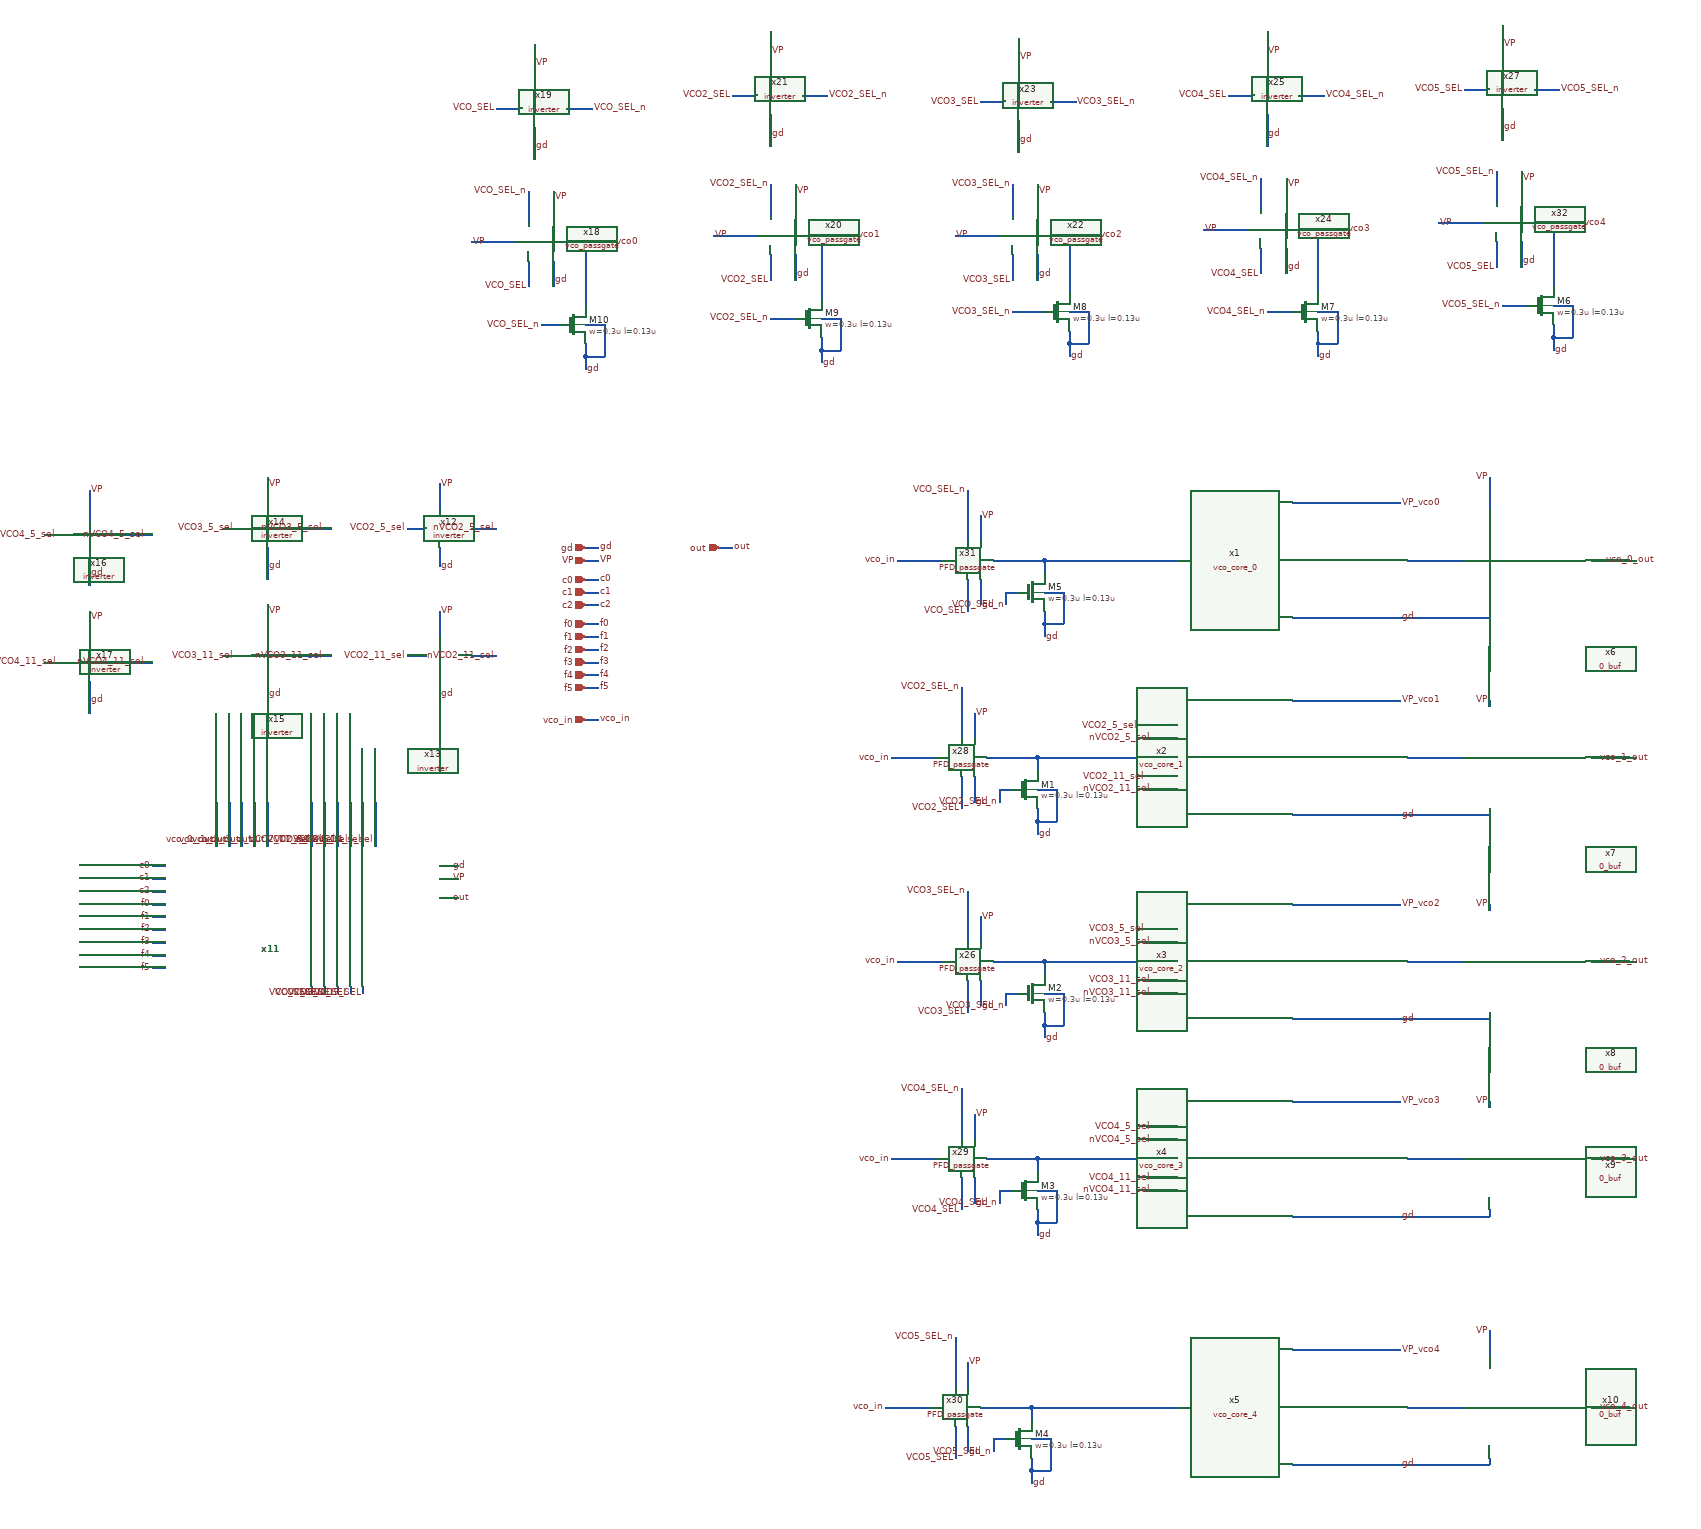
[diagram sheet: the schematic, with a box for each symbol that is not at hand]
v {xschem version=3.4.8RC file_version=1.3}
G {}
K {}
V {}
S {}
F {}
E {}
N 230 -210 320 -210 {lab=#net1}
N 230 100 320 100 {lab=#net2}
N 230 420 320 420 {lab=#net3}
N 230 730 320 730 {lab=#net4}
N 230 1120 320 1120 {lab=#net5}
N 520 -210 580 -210 {lab=vco_0_out}
N 520 100 580 100 {lab=vco_1_out}
N 520 420 580 420 {lab=vco_2_out}
N 520 730 580 730 {lab=vco_3_out}
N 520 1120 580 1120 {lab=vco_4_out}
N -1060 -230 -1040 -230 {lab=gd}
N -1060 -210 -1040 -210 {lab=VP}
N -1060 -160 -1040 -160 {lab=c1}
N -1060 -140 -1040 -140 {lab=c2}
N -1060 -110 -1040 -110 {lab=f0}
N -1060 -90 -1040 -90 {lab=f1}
N -1060 -180 -1040 -180 {lab=c0}
N -1060 -70 -1040 -70 {lab=f2}
N -1060 -50 -1040 -50 {lab=f3}
N -1060 -30 -1040 -30 {lab=f4}
N -1060 -10 -1040 -10 {lab=f5}
N -1290 270 -1270 270 {lab=gd}
N -1290 290 -1270 290 {lab=VP}
N -850 -230 -830 -230 {lab=out}
N -1290 320 -1270 320 {lab=out}
N 50 -120 360 -120 {lab=gd}
N 360 -130 360 -120 {lab=gd}
N 50 190 360 190 {lab=gd}
N 360 180 360 190 {lab=gd}
N 50 510 360 510 {lab=gd}
N 360 500 360 510 {lab=gd}
N 360 810 360 820 {lab=gd}
N 50 1210 360 1210 {lab=gd}
N 360 1200 360 1210 {lab=gd}
N 360 640 360 650 {lab=VP}
N 360 330 360 340 {lab=VP}
N 360 10 360 20 {lab=VP}
N -180 130 -130 130 {lab=VCO2_11_sel}
N -180 150 -130 150 {lab=nVCO2_11_sel}
N -180 470 -130 470 {lab=nVCO3_11_sel}
N -180 780 -130 780 {lab=nVCO4_11_sel}
N -1490 170 -1490 240 {lab=VCO2_11_sel}
N -1470 170 -1470 240 {lab=VCO2_5_sel}
N -1450 170 -1450 240 {lab=VCO3_11_sel}
N -1430 170 -1430 240 {lab=VCO3_5_sel}
N -1410 170 -1410 240 {lab=VCO4_11_sel}
N -1390 170 -1390 240 {lab=VCO4_5_sel}
N -1640 170 -1640 240 {lab=vco_0_out}
N -1620 170 -1620 240 {lab=vco_1_out}
N -1600 170 -1600 240 {lab=vco_2_out}
N -1580 170 -1580 240 {lab=vco_3_out}
N -1560 170 -1560 240 {lab=vco_4_out}
N -1740 290 -1720 290 {lab=c1}
N -1740 310 -1720 310 {lab=c2}
N -1740 330 -1720 330 {lab=f0}
N -1740 350 -1720 350 {lab=f1}
N -1740 270 -1720 270 {lab=c0}
N -1740 370 -1720 370 {lab=f2}
N -1740 390 -1720 390 {lab=f3}
N -1740 410 -1720 410 {lab=f4}
N -1740 430 -1720 430 {lab=f5}
N -1060 40 -1040 40 {lab=vco_in}
N 50 820 360 820 {lab=gd}
N -180 70 -130 70 {lab=nVCO2_5_sel}
N -180 370 -130 370 {lab=VCO3_5_sel}
N -180 390 -130 390 {lab=nVCO3_5_sel}
N -1560 -340 -1560 -290 {lab=VP}
N -1560 -230 -1560 -180 {lab=gd}
N -1510 -260 -1460 -260 {lab=nVCO3_5_sel}
N -1630 -260 -1580 -260 {lab=VCO3_5_sel}
N -1560 -140 -1560 -90 {lab=VP}
N -1560 -30 -1560 20 {lab=gd}
N -1510 -60 -1460 -60 {lab=nVCO3_11_sel}
N -1630 -60 -1580 -60 {lab=VCO3_11_sel}
N -180 680 -130 680 {lab=VCO4_5_sel}
N -180 760 -130 760 {lab=VCO4_11_sel}
N -180 700 -130 700 {lab=nVCO4_5_sel}
N -1840 -220 -1840 -170 {lab=gd}
N -1790 -250 -1740 -250 {lab=nVCO4_5_sel}
N -1910 -250 -1860 -250 {lab=VCO4_5_sel}
N -1840 -130 -1840 -80 {lab=VP}
N -1840 -20 -1840 30 {lab=gd}
N -1790 -50 -1740 -50 {lab=nVCO4_11_sel}
N -1910 -50 -1860 -50 {lab=VCO4_11_sel}
N -1840 -320 -1840 -270 {lab=VP}
N -190 50 -130 50 {lab=VCO2_5_sel}
N -180 450 -130 450 {lab=VCO3_11_sel}
N -1290 -30 -1290 0 {lab=gd}
N -1340 -60 -1310 -60 {lab=VCO2_11_sel}
N -1240 -60 -1200 -60 {lab=nVCO2_11_sel}
N -1290 -130 -1290 -90 {lab=VP}
N -1290 -230 -1290 -200 {lab=gd}
N -1340 -260 -1310 -260 {lab=VCO2_5_sel}
N -1240 -260 -1200 -260 {lab=nVCO2_5_sel}
N -1290 -330 -1290 -290 {lab=VP}
N -1240 -710 -1170 -710 {lab=VP}
N -1060 -710 -1010 -710 {lab=VP_vco0}
N -1200 -920 -1160 -920 {lab=VCO_SEL}
N -1140 -890 -1140 -840 {lab=gd}
N -1140 -1020 -1140 -950 {lab=VP}
N -1090 -920 -1050 -920 {lab=VCO_SEL_n}
N -1150 -680 -1150 -640 {lab=VCO_SEL}
N -1150 -790 -1150 -740 {lab=VCO_SEL_n}
N -1110 -790 -1110 -740 {lab=VP}
N -1110 -680 -1110 -640 {lab=gd}
N -860 -720 -790 -720 {lab=VP}
N -690 -720 -630 -720 {lab=VP_vco1}
N -830 -940 -790 -940 {lab=VCO2_SEL}
N -770 -910 -770 -860 {lab=gd}
N -770 -1040 -770 -970 {lab=VP}
N -720 -940 -680 -940 {lab=VCO2_SEL_n}
N -770 -690 -770 -650 {lab=VCO2_SEL}
N -770 -800 -770 -750 {lab=VCO2_SEL_n}
N -730 -800 -730 -750 {lab=VP}
N -730 -690 -730 -650 {lab=gd}
N -480 -720 -410 -720 {lab=VP}
N -300 -720 -250 -720 {lab=VP_vco2}
N -440 -930 -400 -930 {lab=VCO3_SEL}
N -380 -900 -380 -850 {lab=gd}
N -380 -1030 -380 -960 {lab=VP}
N -330 -930 -290 -930 {lab=VCO3_SEL_n}
N -390 -690 -390 -650 {lab=VCO3_SEL}
N -390 -800 -390 -750 {lab=VCO3_SEL_n}
N -350 -800 -350 -750 {lab=VP}
N -350 -690 -350 -650 {lab=gd}
N -90 -730 -20 -730 {lab=VP}
N 90 -730 140 -730 {lab=VP_vco3}
N -50 -940 -10 -940 {lab=VCO4_SEL}
N 10 -910 10 -860 {lab=gd}
N 10 -1040 10 -970 {lab=VP}
N 60 -940 100 -940 {lab=VCO4_SEL_n}
N 0 -700 0 -660 {lab=VCO4_SEL}
N 0 -810 0 -760 {lab=VCO4_SEL_n}
N 40 -810 40 -760 {lab=VP}
N 40 -700 40 -660 {lab=gd}
N 280 -740 350 -740 {lab=VP}
N 460 -740 510 -740 {lab=VP_vco4}
N 320 -950 360 -950 {lab=VCO5_SEL}
N 380 -920 380 -870 {lab=gd}
N 380 -1050 380 -980 {lab=VP}
N 430 -950 470 -950 {lab=VCO5_SEL_n}
N 370 -710 370 -670 {lab=VCO5_SEL}
N 370 -820 370 -770 {lab=VCO5_SEL_n}
N 410 -820 410 -770 {lab=VP}
N 410 -710 410 -670 {lab=gd}
N 50 -300 220 -300 {lab=VP_vco0}
N 360 -340 360 -290 {lab=VP}
N 50 10 220 10 {lab=VP_vco1}
N 50 330 220 330 {lab=VP_vco2}
N 50 640 220 640 {lab=VP_vco3}
N 50 1030 220 1030 {lab=VP_vco4}
N 360 1000 360 1040 {lab=VP}
N -580 100 -510 100 {lab=vco_in}
N -350 100 -130 100 {lab=#net6}
N -450 30 -450 70 {lab=VP}
N -450 130 -450 170 {lab=gd}
N -350 100 -350 120 {lab=#net6}
N -430 100 -350 100 {lab=#net6}
N -410 150 -390 150 {lab=VCO2_SEL_n}
N -350 200 -350 220 {lab=gd}
N -350 200 -320 200 {lab=gd}
N -350 180 -350 200 {lab=gd}
N -320 150 -320 200 {lab=gd}
N -350 150 -320 150 {lab=gd}
N -470 130 -470 180 {lab=VCO2_SEL}
N -340 420 -130 420 {lab=#net7}
N -350 730 -130 730 {lab=#net8}
N -360 1120 -130 1120 {lab=#net9}
N -470 -10 -470 70 {lab=VCO2_SEL_n}
N 460 -560 460 -540 {lab=gd}
N 460 -560 490 -560 {lab=gd}
N 460 -580 460 -560 {lab=gd}
N 490 -610 490 -560 {lab=gd}
N 460 -610 490 -610 {lab=gd}
N 460 -740 460 -640 {lab=VP_vco4}
N 430 -740 460 -740 {lab=VP_vco4}
N 90 -550 90 -530 {lab=gd}
N 90 -550 120 -550 {lab=gd}
N 90 -570 90 -550 {lab=gd}
N 120 -600 120 -550 {lab=gd}
N 90 -600 120 -600 {lab=gd}
N 90 -730 90 -630 {lab=VP_vco3}
N 60 -730 90 -730 {lab=VP_vco3}
N -300 -550 -300 -530 {lab=gd}
N -300 -550 -270 -550 {lab=gd}
N -300 -570 -300 -550 {lab=gd}
N -270 -600 -270 -550 {lab=gd}
N -300 -600 -270 -600 {lab=gd}
N -690 -540 -690 -520 {lab=gd}
N -690 -540 -660 -540 {lab=gd}
N -690 -560 -690 -540 {lab=gd}
N -660 -590 -660 -540 {lab=gd}
N -690 -590 -660 -590 {lab=gd}
N -690 -720 -690 -620 {lab=VP_vco1}
N -710 -720 -690 -720 {lab=VP_vco1}
N -1060 -530 -1060 -510 {lab=gd}
N -1060 -530 -1030 -530 {lab=gd}
N -1060 -550 -1060 -530 {lab=gd}
N -1030 -580 -1030 -530 {lab=gd}
N -1060 -580 -1030 -580 {lab=gd}
N -1060 -710 -1060 -610 {lab=VP_vco0}
N -1090 -710 -1060 -710 {lab=VP_vco0}
N -1130 -580 -1100 -580 {lab=VCO_SEL_n}
N -770 -590 -730 -590 {lab=VCO2_SEL_n}
N -390 -600 -340 -600 {lab=VCO3_SEL_n}
N 10 -600 50 -600 {lab=VCO4_SEL_n}
N 380 -610 420 -610 {lab=VCO5_SEL_n}
N -300 -720 -300 -630 {lab=VP_vco2}
N -330 -720 -300 -720 {lab=VP_vco2}
N -410 150 -410 170 {lab=VCO2_SEL_n}
N -570 420 -500 420 {lab=vco_in}
N -440 350 -440 390 {lab=VP}
N -440 450 -440 490 {lab=gd}
N -340 420 -340 440 {lab=#net7}
N -420 420 -340 420 {lab=#net7}
N -400 470 -380 470 {lab=VCO3_SEL_n}
N -340 520 -340 540 {lab=gd}
N -340 520 -310 520 {lab=gd}
N -340 500 -340 520 {lab=gd}
N -310 470 -310 520 {lab=gd}
N -340 470 -310 470 {lab=gd}
N -460 450 -460 500 {lab=VCO3_SEL}
N -460 310 -460 390 {lab=VCO3_SEL_n}
N -400 470 -400 490 {lab=VCO3_SEL_n}
N -580 730 -510 730 {lab=vco_in}
N -450 660 -450 700 {lab=VP}
N -450 760 -450 800 {lab=gd}
N -350 730 -350 750 {lab=#net8}
N -430 730 -350 730 {lab=#net8}
N -410 780 -390 780 {lab=VCO4_SEL_n}
N -350 830 -350 850 {lab=gd}
N -350 830 -320 830 {lab=gd}
N -350 810 -350 830 {lab=gd}
N -320 780 -320 830 {lab=gd}
N -350 780 -320 780 {lab=gd}
N -470 760 -470 810 {lab=VCO4_SEL}
N -470 620 -470 700 {lab=VCO4_SEL_n}
N -410 780 -410 800 {lab=VCO4_SEL_n}
N -590 1120 -520 1120 {lab=vco_in}
N -460 1050 -460 1090 {lab=VP}
N -460 1150 -460 1190 {lab=gd}
N -360 1120 -360 1140 {lab=#net9}
N -440 1120 -360 1120 {lab=#net9}
N -420 1170 -400 1170 {lab=VCO5_SEL_n}
N -360 1220 -360 1240 {lab=gd}
N -360 1220 -330 1220 {lab=gd}
N -360 1200 -360 1220 {lab=gd}
N -330 1170 -330 1220 {lab=gd}
N -360 1170 -330 1170 {lab=gd}
N -480 1150 -480 1200 {lab=VCO5_SEL}
N -480 1010 -480 1090 {lab=VCO5_SEL_n}
N -420 1170 -420 1190 {lab=VCO5_SEL_n}
N -570 -210 -500 -210 {lab=vco_in}
N -440 -280 -440 -240 {lab=VP}
N -440 -180 -440 -140 {lab=gd}
N -340 -210 -340 -190 {lab=#net10}
N -420 -210 -340 -210 {lab=#net10}
N -400 -160 -380 -160 {lab=VCO_SEL_n}
N -340 -110 -340 -90 {lab=gd}
N -340 -110 -310 -110 {lab=gd}
N -340 -130 -340 -110 {lab=gd}
N -310 -160 -310 -110 {lab=gd}
N -340 -160 -310 -160 {lab=gd}
N -460 -180 -460 -130 {lab=VCO_SEL}
N -460 -320 -460 -240 {lab=VCO_SEL_n}
N -400 -160 -400 -140 {lab=VCO_SEL_n}
N -340 -210 -130 -210 {lab=#net10}
N -1490 460 -1490 470 {lab=VCO_SEL}
N -1470 460 -1470 470 {lab=VCO2_SEL}
N -1450 460 -1450 470 {lab=VCO3_SEL}
N -1430 460 -1430 470 {lab=VCO4_SEL}
N -1410 460 -1410 470 {lab=VCO5_SEL}
C {/foss/designs/CHIP-PLL/schematics/vco/vco_cell/vco_core_0.sym} 50 -210 0 0 {name=x1}
C {/foss/designs/CHIP-PLL/schematics/vco/vco_cell/vco_core_1.sym} 50 100 0 0 {name=x2}
C {/foss/designs/CHIP-PLL/schematics/vco/vco_cell/vco_core_2.sym} 50 420 0 0 {name=x3}
C {/foss/designs/CHIP-PLL/schematics/vco/vco_cell/vco_core_3.sym} 50 730 0 0 {name=x4}
C {/foss/designs/CHIP-PLL/schematics/vco/vco_cell/vco_core_4.sym} 50 1120 0 0 {name=x5}
C {/foss/designs/CHIP-PLL/schematics/vco/vco_cell/0_buf.sym} 400 -120 0 0 {name=x6}
C {/foss/designs/CHIP-PLL/schematics/vco/vco_cell/0_buf.sym} 400 190 0 0 {name=x7}
C {/foss/designs/CHIP-PLL/schematics/vco/vco_cell/0_buf.sym} 400 510 0 0 {name=x8}
C {/foss/designs/CHIP-PLL/schematics/vco/vco_cell/0_buf.sym} 400 820 0 0 {name=x9}
C {/foss/designs/CHIP-PLL/schematics/vco/vco_cell/0_buf.sym} 400 1210 0 0 {name=x10}
C {/foss/designs/CHIP-PLL/schematics/divider/schematics/VCO_MUX_and_decoder.sym} -1570 400 0 0 {name=x11}
C {iopin.sym} -1060 -230 2 0 {name=p46 lab=gd}
C {lab_wire.sym} -1040 -230 2 0 {name=p53 sig_type=std_logic lab=gd}
C {iopin.sym} -1060 -210 2 0 {name=p54 lab=VP}
C {ipin.sym} -1060 -160 0 0 {name=p2 lab=c1}
C {lab_wire.sym} -1040 -160 2 0 {name=p56 sig_type=std_logic lab=c1}
C {ipin.sym} -1060 -140 0 0 {name=p57 lab=c2}
C {lab_wire.sym} -1040 -140 2 0 {name=p58 sig_type=std_logic lab=c2}
C {ipin.sym} -1060 -110 0 0 {name=p59 lab=f0}
C {lab_wire.sym} -1040 -110 2 0 {name=p60 sig_type=std_logic lab=f0}
C {ipin.sym} -1060 -90 0 0 {name=p61 lab=f1}
C {lab_wire.sym} -1040 -90 2 0 {name=p63 sig_type=std_logic lab=f1}
C {ipin.sym} -1060 -180 0 0 {name=p20 lab=c0}
C {lab_wire.sym} -1040 -180 2 0 {name=p21 sig_type=std_logic lab=c0}
C {lab_wire.sym} -1040 -210 2 0 {name=p1 sig_type=std_logic lab=VP}
C {ipin.sym} -1060 -70 0 0 {name=p19 lab=f2}
C {lab_wire.sym} -1040 -70 2 0 {name=p22 sig_type=std_logic lab=f2}
C {ipin.sym} -1060 -50 0 0 {name=p23 lab=f3}
C {lab_wire.sym} -1040 -50 2 0 {name=p24 sig_type=std_logic lab=f3}
C {ipin.sym} -1060 -30 0 0 {name=p25 lab=f4}
C {lab_wire.sym} -1040 -30 2 0 {name=p26 sig_type=std_logic lab=f4}
C {ipin.sym} -1060 -10 0 0 {name=p27 lab=f5}
C {lab_wire.sym} -1040 -10 2 0 {name=p28 sig_type=std_logic lab=f5}
C {lab_wire.sym} -1270 270 2 0 {name=p3 sig_type=std_logic lab=gd}
C {lab_wire.sym} -1270 290 2 0 {name=p4 sig_type=std_logic lab=VP}
C {opin.sym} -850 -230 0 1 {name=p55 lab=out}
C {lab_wire.sym} -830 -230 2 0 {name=p62 sig_type=std_logic lab=out}
C {lab_wire.sym} -1270 320 2 0 {name=p5 sig_type=std_logic lab=out}
C {lab_wire.sym} 220 10 2 0 {name=p6 sig_type=std_logic lab=VP_vco1}
C {lab_wire.sym} 220 -300 2 0 {name=p7 sig_type=std_logic lab=VP_vco0}
C {lab_wire.sym} 220 330 2 0 {name=p8 sig_type=std_logic lab=VP_vco2}
C {lab_wire.sym} 220 640 2 0 {name=p9 sig_type=std_logic lab=VP_vco3}
C {lab_wire.sym} 220 1030 2 0 {name=p10 sig_type=std_logic lab=VP_vco4}
C {lab_wire.sym} 220 -120 2 0 {name=p11 sig_type=std_logic lab=gd}
C {lab_wire.sym} 220 190 2 0 {name=p12 sig_type=std_logic lab=gd}
C {lab_wire.sym} 220 510 2 0 {name=p13 sig_type=std_logic lab=gd}
C {lab_wire.sym} 220 820 2 0 {name=p14 sig_type=std_logic lab=gd}
C {lab_wire.sym} 220 1210 2 0 {name=p15 sig_type=std_logic lab=gd}
C {lab_wire.sym} -180 130 2 1 {name=p95 sig_type=std_logic lab=VCO2_11_sel}
C {lab_wire.sym} -190 50 2 1 {name=p99 sig_type=std_logic lab=VCO2_5_sel}
C {lab_wire.sym} -180 370 2 1 {name=p17 sig_type=std_logic lab=VCO3_5_sel}
C {lab_wire.sym} -1490 230 3 1 {name=p33 sig_type=std_logic lab=VCO2_11_sel}
C {lab_wire.sym} -1470 230 3 1 {name=p35 sig_type=std_logic lab=VCO2_5_sel}
C {lab_wire.sym} -1450 230 3 1 {name=p36 sig_type=std_logic lab=VCO3_11_sel}
C {lab_wire.sym} -1430 230 3 1 {name=p37 sig_type=std_logic lab=VCO3_5_sel}
C {lab_wire.sym} -1410 230 3 1 {name=p38 sig_type=std_logic lab=VCO4_11_sel}
C {lab_wire.sym} -1390 230 3 1 {name=p39 sig_type=std_logic lab=VCO4_5_sel}
C {lab_wire.sym} 540 -210 2 0 {name=p34 sig_type=std_logic lab=vco_0_out}
C {lab_wire.sym} 530 100 2 0 {name=p41 sig_type=std_logic lab=vco_1_out}
C {lab_wire.sym} 530 420 2 0 {name=p42 sig_type=std_logic lab=vco_2_out}
C {lab_wire.sym} 530 730 2 0 {name=p43 sig_type=std_logic lab=vco_3_out}
C {lab_wire.sym} 530 1120 2 0 {name=p44 sig_type=std_logic lab=vco_4_out}
C {lab_wire.sym} -1640 230 3 1 {name=p45 sig_type=std_logic lab=vco_0_out}
C {lab_wire.sym} -1620 230 3 1 {name=p47 sig_type=std_logic lab=vco_1_out}
C {lab_wire.sym} -1600 230 3 1 {name=p48 sig_type=std_logic lab=vco_2_out}
C {lab_wire.sym} -1580 230 3 1 {name=p49 sig_type=std_logic lab=vco_3_out}
C {lab_wire.sym} -1560 230 3 1 {name=p50 sig_type=std_logic lab=vco_4_out}
C {lab_wire.sym} -1740 290 2 1 {name=p51 sig_type=std_logic lab=c1}
C {lab_wire.sym} -1740 310 2 1 {name=p52 sig_type=std_logic lab=c2}
C {lab_wire.sym} -1740 330 2 1 {name=p64 sig_type=std_logic lab=f0}
C {lab_wire.sym} -1740 350 2 1 {name=p65 sig_type=std_logic lab=f1}
C {lab_wire.sym} -1740 270 2 1 {name=p66 sig_type=std_logic lab=c0}
C {lab_wire.sym} -1740 370 2 1 {name=p67 sig_type=std_logic lab=f2}
C {lab_wire.sym} -1740 390 2 1 {name=p68 sig_type=std_logic lab=f3}
C {lab_wire.sym} -1740 410 2 1 {name=p69 sig_type=std_logic lab=f4}
C {lab_wire.sym} -1740 430 2 1 {name=p70 sig_type=std_logic lab=f5}
C {ipin.sym} -1060 40 0 0 {name=p30 lab=vco_in}
C {lab_wire.sym} -1040 40 2 0 {name=p31 sig_type=std_logic lab=vco_in}
C {lab_wire.sym} -580 100 2 1 {name=p72 sig_type=std_logic lab=vco_in}
C {/foss/designs/CHIP-PLL/schematics/divider/schematics/inverter.sym} -1290 -260 0 0 {name=x12}
C {lab_wire.sym} -1290 -330 2 0 {name=p32 sig_type=std_logic lab=VP}
C {lab_wire.sym} -1290 -200 2 0 {name=p40 sig_type=std_logic lab=gd}
C {lab_wire.sym} -1340 -260 2 1 {name=p76 sig_type=std_logic lab=VCO2_5_sel}
C {lab_wire.sym} -1200 -260 2 1 {name=p77 sig_type=std_logic lab=nVCO2_5_sel}
C {lab_wire.sym} -170 70 2 1 {name=p78 sig_type=std_logic lab=nVCO2_5_sel}
C {/foss/designs/CHIP-PLL/schematics/divider/schematics/inverter.sym} -1290 -60 0 0 {name=x13}
C {lab_wire.sym} -1290 -130 2 0 {name=p79 sig_type=std_logic lab=VP}
C {lab_wire.sym} -1290 0 2 0 {name=p80 sig_type=std_logic lab=gd}
C {lab_wire.sym} -1340 -60 2 1 {name=p81 sig_type=std_logic lab=VCO2_11_sel}
C {lab_wire.sym} -1200 -60 2 1 {name=p82 sig_type=std_logic lab=nVCO2_11_sel}
C {lab_wire.sym} -170 150 2 1 {name=p83 sig_type=std_logic lab=nVCO2_11_sel}
C {lab_wire.sym} -170 450 2 1 {name=p16 sig_type=std_logic lab=VCO3_11_sel}
C {lab_wire.sym} -170 390 2 1 {name=p29 sig_type=std_logic lab=nVCO3_5_sel}
C {lab_wire.sym} -170 470 2 1 {name=p73 sig_type=std_logic lab=nVCO3_11_sel}
C {/foss/designs/CHIP-PLL/schematics/divider/schematics/inverter.sym} -1560 -260 0 0 {name=x14}
C {lab_wire.sym} -1560 -330 2 0 {name=p74 sig_type=std_logic lab=VP}
C {lab_wire.sym} -1560 -200 2 0 {name=p84 sig_type=std_logic lab=gd}
C {lab_wire.sym} -1610 -260 2 1 {name=p85 sig_type=std_logic lab=VCO3_5_sel}
C {lab_wire.sym} -1470 -260 2 1 {name=p86 sig_type=std_logic lab=nVCO3_5_sel}
C {/foss/designs/CHIP-PLL/schematics/divider/schematics/inverter.sym} -1560 -60 0 0 {name=x15}
C {lab_wire.sym} -1560 -130 2 0 {name=p87 sig_type=std_logic lab=VP}
C {lab_wire.sym} -1560 0 2 0 {name=p88 sig_type=std_logic lab=gd}
C {lab_wire.sym} -1610 -60 2 1 {name=p89 sig_type=std_logic lab=VCO3_11_sel}
C {lab_wire.sym} -1470 -60 2 1 {name=p90 sig_type=std_logic lab=nVCO3_11_sel}
C {lab_wire.sym} -170 760 2 1 {name=p91 sig_type=std_logic lab=VCO4_11_sel}
C {lab_wire.sym} -170 680 2 1 {name=p92 sig_type=std_logic lab=VCO4_5_sel}
C {lab_wire.sym} -170 700 2 1 {name=p94 sig_type=std_logic lab=nVCO4_5_sel}
C {lab_wire.sym} -170 780 2 1 {name=p96 sig_type=std_logic lab=nVCO4_11_sel}
C {/foss/designs/CHIP-PLL/schematics/divider/schematics/inverter.sym} -1840 -250 0 0 {name=x16}
C {lab_wire.sym} -1840 -320 2 0 {name=p97 sig_type=std_logic lab=VP}
C {lab_wire.sym} -1840 -190 2 0 {name=p98 sig_type=std_logic lab=gd}
C {lab_wire.sym} -1890 -250 2 1 {name=p100 sig_type=std_logic lab=VCO4_5_sel}
C {lab_wire.sym} -1750 -250 2 1 {name=p101 sig_type=std_logic lab=nVCO4_5_sel}
C {/foss/designs/CHIP-PLL/schematics/divider/schematics/inverter.sym} -1840 -50 0 0 {name=x17}
C {lab_wire.sym} -1840 -120 2 0 {name=p102 sig_type=std_logic lab=VP}
C {lab_wire.sym} -1840 10 2 0 {name=p103 sig_type=std_logic lab=gd}
C {lab_wire.sym} -1890 -50 2 1 {name=p104 sig_type=std_logic lab=VCO4_11_sel}
C {lab_wire.sym} -1750 -50 2 1 {name=p105 sig_type=std_logic lab=nVCO4_11_sel}
C {/foss/designs/CHIP-PLL/schematics/divider/schematics/inverter.sym} -1140 -920 0 0 {name=x19}
C {lab_wire.sym} -1140 -990 2 0 {name=p107 sig_type=std_logic lab=VP}
C {lab_wire.sym} -1140 -860 2 0 {name=p108 sig_type=std_logic lab=gd}
C {lab_wire.sym} -1110 -650 2 0 {name=p110 sig_type=std_logic lab=gd}
C {lab_wire.sym} -1110 -780 2 0 {name=p111 sig_type=std_logic lab=VP}
C {lab_wire.sym} -1240 -710 2 0 {name=p112 sig_type=std_logic lab=VP}
C {lab_wire.sym} -1040 -710 2 0 {name=p113 sig_type=std_logic lab=VP_vco0}
C {/foss/designs/CHIP-PLL/schematics/divider/schematics/inverter.sym} -770 -940 0 0 {name=x21}
C {lab_wire.sym} -770 -1010 2 0 {name=p117 sig_type=std_logic lab=VP}
C {lab_wire.sym} -770 -880 2 0 {name=p118 sig_type=std_logic lab=gd}
C {lab_wire.sym} -730 -660 2 0 {name=p120 sig_type=std_logic lab=gd}
C {lab_wire.sym} -730 -790 2 0 {name=p121 sig_type=std_logic lab=VP}
C {lab_wire.sym} -860 -720 2 0 {name=p122 sig_type=std_logic lab=VP}
C {lab_wire.sym} -660 -720 2 0 {name=p123 sig_type=std_logic lab=VP_vco1}
C {/foss/designs/CHIP-PLL/schematics/divider/schematics/inverter.sym} -380 -930 0 0 {name=x23}
C {lab_wire.sym} -380 -1000 2 0 {name=p127 sig_type=std_logic lab=VP}
C {lab_wire.sym} -380 -870 2 0 {name=p128 sig_type=std_logic lab=gd}
C {lab_wire.sym} -350 -660 2 0 {name=p130 sig_type=std_logic lab=gd}
C {lab_wire.sym} -350 -790 2 0 {name=p131 sig_type=std_logic lab=VP}
C {lab_wire.sym} -480 -720 2 0 {name=p132 sig_type=std_logic lab=VP}
C {lab_wire.sym} -280 -720 2 0 {name=p133 sig_type=std_logic lab=VP_vco2}
C {/foss/designs/CHIP-PLL/schematics/divider/schematics/inverter.sym} 10 -940 0 0 {name=x25}
C {lab_wire.sym} 10 -1010 2 0 {name=p137 sig_type=std_logic lab=VP}
C {lab_wire.sym} 10 -880 2 0 {name=p138 sig_type=std_logic lab=gd}
C {lab_wire.sym} 40 -670 2 0 {name=p140 sig_type=std_logic lab=gd}
C {lab_wire.sym} 40 -800 2 0 {name=p141 sig_type=std_logic lab=VP}
C {lab_wire.sym} -90 -730 2 0 {name=p142 sig_type=std_logic lab=VP}
C {lab_wire.sym} 110 -730 2 0 {name=p143 sig_type=std_logic lab=VP_vco3}
C {/foss/designs/CHIP-PLL/schematics/divider/schematics/inverter.sym} 380 -950 0 0 {name=x27}
C {lab_wire.sym} 380 -1020 2 0 {name=p147 sig_type=std_logic lab=VP}
C {lab_wire.sym} 380 -890 2 0 {name=p148 sig_type=std_logic lab=gd}
C {lab_wire.sym} 410 -680 2 0 {name=p150 sig_type=std_logic lab=gd}
C {lab_wire.sym} 410 -810 2 0 {name=p151 sig_type=std_logic lab=VP}
C {lab_wire.sym} 280 -740 2 0 {name=p152 sig_type=std_logic lab=VP}
C {lab_wire.sym} 480 -740 2 0 {name=p153 sig_type=std_logic lab=VP_vco4}
C {lab_wire.sym} 360 1000 0 0 {name=p18 sig_type=std_logic lab=VP}
C {lab_wire.sym} 360 640 0 0 {name=p93 sig_type=std_logic lab=VP}
C {lab_wire.sym} 360 330 0 0 {name=p162 sig_type=std_logic lab=VP}
C {lab_wire.sym} 360 10 0 0 {name=p163 sig_type=std_logic lab=VP}
C {lab_wire.sym} 360 -340 0 0 {name=p164 sig_type=std_logic lab=VP}
C {lab_wire.sym} -450 170 2 0 {name=p161 sig_type=std_logic lab=gd}
C {lab_wire.sym} -450 30 2 0 {name=p165 sig_type=std_logic lab=VP}
C {sg13g2_pr/sg13_lv_nmos.sym} -370 150 0 0 {name=M1
l=0.13u
w=0.3u
ng=1
m=1
mm_ok=1
model=sg13_lv_nmos
spiceprefix=X
}
C {lab_wire.sym} -350 220 2 0 {name=p166 sig_type=std_logic lab=gd}
C {lab_wire.sym} -470 180 2 1 {name=p198 sig_type=std_logic lab=VCO2_SEL}
C {sg13g2_pr/sg13_lv_nmos.sym} 440 -610 0 0 {name=M6
l=0.13u
w=0.3u
ng=1
m=1
mm_ok=1
model=sg13_lv_nmos
spiceprefix=X
}
C {lab_wire.sym} 460 -540 2 0 {name=p216 sig_type=std_logic lab=gd}
C {sg13g2_pr/sg13_lv_nmos.sym} 70 -600 0 0 {name=M7
l=0.13u
w=0.3u
ng=1
m=1
mm_ok=1
model=sg13_lv_nmos
spiceprefix=X
}
C {lab_wire.sym} 90 -530 2 0 {name=p217 sig_type=std_logic lab=gd}
C {sg13g2_pr/sg13_lv_nmos.sym} -320 -600 0 0 {name=M8
l=0.13u
w=0.3u
ng=1
m=1
mm_ok=1
model=sg13_lv_nmos
spiceprefix=X
}
C {lab_wire.sym} -300 -530 2 0 {name=p218 sig_type=std_logic lab=gd}
C {sg13g2_pr/sg13_lv_nmos.sym} -710 -590 0 0 {name=M9
l=0.13u
w=0.3u
ng=1
m=1
mm_ok=1
model=sg13_lv_nmos
spiceprefix=X
}
C {lab_wire.sym} -690 -520 2 0 {name=p219 sig_type=std_logic lab=gd}
C {sg13g2_pr/sg13_lv_nmos.sym} -1080 -580 0 0 {name=M10
l=0.13u
w=0.3u
ng=1
m=1
mm_ok=1
model=sg13_lv_nmos
spiceprefix=X
}
C {lab_wire.sym} -1060 -510 2 0 {name=p220 sig_type=std_logic lab=gd}
C {/foss/designs/CHIP-PLL/schematics/PFD/PFD_passgate.sym} -470 100 0 1 {name=x28}
C {lab_wire.sym} -470 -10 2 1 {name=p156 sig_type=std_logic lab=VCO2_SEL_n}
C {lab_wire.sym} -410 170 1 1 {name=p183 sig_type=std_logic lab=VCO2_SEL_n}
C {lab_wire.sym} -570 420 2 1 {name=p71 sig_type=std_logic lab=vco_in}
C {lab_wire.sym} -440 490 2 0 {name=p75 sig_type=std_logic lab=gd}
C {lab_wire.sym} -440 350 2 0 {name=p167 sig_type=std_logic lab=VP}
C {sg13g2_pr/sg13_lv_nmos.sym} -360 470 0 0 {name=M2
l=0.13u
w=0.3u
ng=1
m=1
mm_ok=1
model=sg13_lv_nmos
spiceprefix=X
}
C {lab_wire.sym} -340 540 2 0 {name=p168 sig_type=std_logic lab=gd}
C {lab_wire.sym} -460 500 2 1 {name=p169 sig_type=std_logic lab=VCO3_SEL}
C {/foss/designs/CHIP-PLL/schematics/PFD/PFD_passgate.sym} -460 420 0 1 {name=x26}
C {lab_wire.sym} -460 310 2 1 {name=p170 sig_type=std_logic lab=VCO3_SEL_n}
C {lab_wire.sym} -400 490 1 1 {name=p171 sig_type=std_logic lab=VCO3_SEL_n}
C {lab_wire.sym} -580 730 2 1 {name=p172 sig_type=std_logic lab=vco_in}
C {lab_wire.sym} -450 800 2 0 {name=p173 sig_type=std_logic lab=gd}
C {lab_wire.sym} -450 660 2 0 {name=p174 sig_type=std_logic lab=VP}
C {sg13g2_pr/sg13_lv_nmos.sym} -370 780 0 0 {name=M3
l=0.13u
w=0.3u
ng=1
m=1
mm_ok=1
model=sg13_lv_nmos
spiceprefix=X
}
C {lab_wire.sym} -350 850 2 0 {name=p175 sig_type=std_logic lab=gd}
C {lab_wire.sym} -470 810 2 1 {name=p176 sig_type=std_logic lab=VCO4_SEL}
C {/foss/designs/CHIP-PLL/schematics/PFD/PFD_passgate.sym} -470 730 0 1 {name=x29}
C {lab_wire.sym} -470 620 2 1 {name=p177 sig_type=std_logic lab=VCO4_SEL_n}
C {lab_wire.sym} -410 800 1 1 {name=p178 sig_type=std_logic lab=VCO4_SEL_n}
C {lab_wire.sym} -590 1120 2 1 {name=p179 sig_type=std_logic lab=vco_in}
C {lab_wire.sym} -460 1190 2 0 {name=p180 sig_type=std_logic lab=gd}
C {lab_wire.sym} -460 1050 2 0 {name=p181 sig_type=std_logic lab=VP}
C {sg13g2_pr/sg13_lv_nmos.sym} -380 1170 0 0 {name=M4
l=0.13u
w=0.3u
ng=1
m=1
mm_ok=1
model=sg13_lv_nmos
spiceprefix=X
}
C {lab_wire.sym} -360 1240 2 0 {name=p182 sig_type=std_logic lab=gd}
C {lab_wire.sym} -480 1200 2 1 {name=p184 sig_type=std_logic lab=VCO5_SEL}
C {/foss/designs/CHIP-PLL/schematics/PFD/PFD_passgate.sym} -480 1120 0 1 {name=x30}
C {lab_wire.sym} -480 1010 2 1 {name=p185 sig_type=std_logic lab=VCO5_SEL_n}
C {lab_wire.sym} -420 1190 1 1 {name=p186 sig_type=std_logic lab=VCO5_SEL_n}
C {lab_wire.sym} -570 -210 2 1 {name=p187 sig_type=std_logic lab=vco_in}
C {lab_wire.sym} -440 -140 2 0 {name=p188 sig_type=std_logic lab=gd}
C {lab_wire.sym} -440 -280 2 0 {name=p189 sig_type=std_logic lab=VP}
C {sg13g2_pr/sg13_lv_nmos.sym} -360 -160 0 0 {name=M5
l=0.13u
w=0.3u
ng=1
m=1
mm_ok=1
model=sg13_lv_nmos
spiceprefix=X
}
C {lab_wire.sym} -340 -90 2 0 {name=p190 sig_type=std_logic lab=gd}
C {lab_wire.sym} -460 -130 2 1 {name=p191 sig_type=std_logic lab=VCO_SEL}
C {/foss/designs/CHIP-PLL/schematics/PFD/PFD_passgate.sym} -460 -210 0 1 {name=x31}
C {lab_wire.sym} -460 -320 2 1 {name=p192 sig_type=std_logic lab=VCO_SEL_n}
C {lab_wire.sym} -400 -140 1 1 {name=p193 sig_type=std_logic lab=VCO_SEL_n}
C {lab_wire.sym} -1050 -920 0 1 {name=p157 sig_type=std_logic lab=VCO_SEL_n}
C {lab_wire.sym} -1200 -920 2 1 {name=p158 sig_type=std_logic lab=VCO_SEL}
C {lab_wire.sym} -1130 -580 2 1 {name=p106 sig_type=std_logic lab=VCO_SEL_n}
C {lab_wire.sym} -1150 -790 2 1 {name=p109 sig_type=std_logic lab=VCO_SEL_n}
C {lab_wire.sym} -1150 -640 2 1 {name=p114 sig_type=std_logic lab=VCO_SEL}
C {lab_wire.sym} -680 -940 0 1 {name=p115 sig_type=std_logic lab=VCO2_SEL_n}
C {lab_wire.sym} -830 -940 2 1 {name=p116 sig_type=std_logic lab=VCO2_SEL}
C {lab_wire.sym} -770 -650 2 1 {name=p119 sig_type=std_logic lab=VCO2_SEL}
C {lab_wire.sym} -770 -800 2 1 {name=p124 sig_type=std_logic lab=VCO2_SEL_n}
C {lab_wire.sym} -770 -590 2 1 {name=p125 sig_type=std_logic lab=VCO2_SEL_n}
C {lab_wire.sym} -290 -930 0 1 {name=p126 sig_type=std_logic lab=VCO3_SEL_n}
C {lab_wire.sym} -390 -800 2 1 {name=p129 sig_type=std_logic lab=VCO3_SEL_n}
C {lab_wire.sym} -390 -600 2 1 {name=p134 sig_type=std_logic lab=VCO3_SEL_n}
C {lab_wire.sym} -390 -650 2 1 {name=p135 sig_type=std_logic lab=VCO3_SEL}
C {lab_wire.sym} -440 -930 2 1 {name=p159 sig_type=std_logic lab=VCO3_SEL}
C {lab_wire.sym} -50 -940 2 1 {name=p136 sig_type=std_logic lab=VCO4_SEL}
C {lab_wire.sym} 100 -940 0 1 {name=p139 sig_type=std_logic lab=VCO4_SEL_n}
C {lab_wire.sym} 0 -660 2 1 {name=p144 sig_type=std_logic lab=VCO4_SEL}
C {lab_wire.sym} 0 -810 2 1 {name=p145 sig_type=std_logic lab=VCO4_SEL_n}
C {lab_wire.sym} 10 -600 2 1 {name=p160 sig_type=std_logic lab=VCO4_SEL_n}
C {lab_wire.sym} 370 -670 2 1 {name=p146 sig_type=std_logic lab=VCO5_SEL}
C {lab_wire.sym} 470 -950 0 1 {name=p149 sig_type=std_logic lab=VCO5_SEL_n}
C {lab_wire.sym} 370 -820 2 1 {name=p154 sig_type=std_logic lab=VCO5_SEL_n}
C {lab_wire.sym} 380 -610 2 1 {name=p155 sig_type=std_logic lab=VCO5_SEL_n}
C {lab_wire.sym} 320 -950 2 1 {name=p194 sig_type=std_logic lab=VCO5_SEL}
C {lab_wire.sym} -1490 470 1 1 {name=p195 sig_type=std_logic lab=VCO_SEL}
C {lab_wire.sym} -1470 470 1 1 {name=p196 sig_type=std_logic lab=VCO2_SEL}
C {lab_wire.sym} -1450 470 1 1 {name=p197 sig_type=std_logic lab=VCO3_SEL}
C {lab_wire.sym} -1430 470 1 1 {name=p199 sig_type=std_logic lab=VCO4_SEL}
C {lab_wire.sym} -1410 470 1 1 {name=p200 sig_type=std_logic lab=VCO5_SEL}
C {/foss/designs/CHIP-PLL/schematics/vco/vco_cell/vco_passgate.sym} -1150 -690 0 0 {name=x18}
C {/foss/designs/CHIP-PLL/schematics/vco/vco_cell/vco_passgate.sym} -770 -700 0 0 {name=x20}
C {/foss/designs/CHIP-PLL/schematics/vco/vco_cell/vco_passgate.sym} -390 -700 0 0 {name=x22}
C {/foss/designs/CHIP-PLL/schematics/vco/vco_cell/vco_passgate.sym} 0 -710 0 0 {name=x24}
C {/foss/designs/CHIP-PLL/schematics/vco/vco_cell/vco_passgate.sym} 370 -720 0 0 {name=x32}
